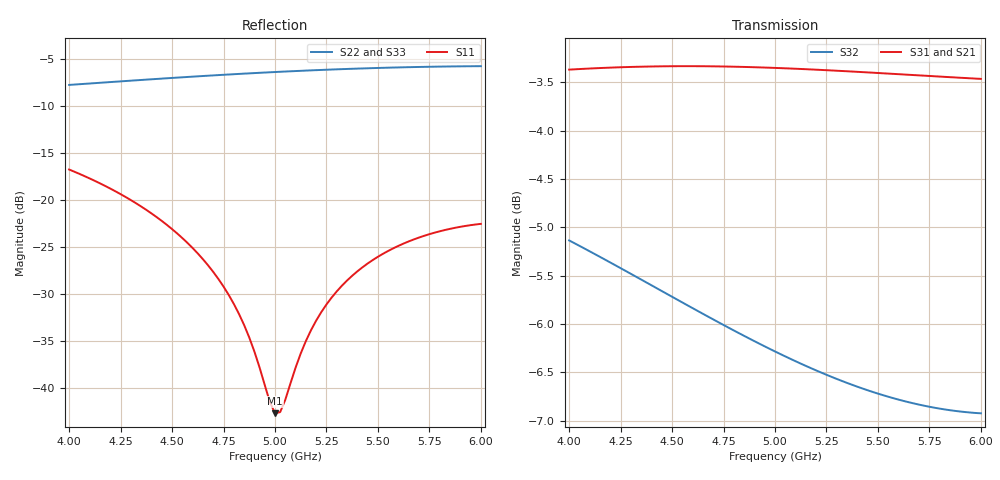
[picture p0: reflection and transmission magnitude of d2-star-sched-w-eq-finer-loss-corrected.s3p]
! yapnr Order 0 prediction d2-star-sched-w-eq-finer: predictions/D2/runs/d2-star-sched/finer.s3p, loss-corrected
! substrate W-eq; coupon model OSHPARK-4L-FR408HR; correction: ratio (port line)
! |S21|, |S31| (and S12, S13) scaled, phases kept; 50 ohm, e^(+jwt)
# GHz S RI R 50
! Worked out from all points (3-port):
!   81 points, 4 GHz to 6 GHz, reference 50 ohm
!   strongest paths, dB at 4 GHz, 4.5 GHz, 5 GHz, 5.5 GHz, 6 GHz:
!     S31: -3.4, -3.3, -3.4, -3.4, -3.5
!     S21: -3.4, -3.3, -3.4, -3.4, -3.5
!     S32: -5.1, -5.7, -6.3, -6.7, -6.9
!   lowest |S11| = -42.7 dB at 5 GHz (marker M1), VSWR 1.01, Z = 49.7 + j0.675 ohm
!   |S11| at or under -10 dB: start of sweep to end of sweep
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4  0.0376 0.1407  -0.6595 -0.1602  -0.6595 -0.1602
   -0.6593 -0.1607  0.3541 -0.2086  -0.4548 0.3158
   -0.6593 -0.1607  -0.4548 0.3158  0.3541 -0.2086
4.375  0.0419 0.0782  -0.6795 0.0395  -0.6795 0.0395
       -0.68 0.0385  0.2757 -0.3411  -0.3106 0.4253
       -0.68 0.0385  -0.3106 0.4253  0.2757 -0.3411
4.65  0.0281 0.0395  -0.6545 0.1863  -0.6545 0.1863
      -0.6557 0.1852  0.1915 -0.4165  -0.1956 0.4681
      -0.6557 0.1852  -0.1956 0.4681  0.1915 -0.4165
4.825  0.0139 0.0205  -0.6215 0.2754  -0.6215 0.2754
       -0.6231 0.2745  0.1292 -0.4523  -0.123 0.4803
       -0.6231 0.2745  -0.123 0.4803  0.1292 -0.4523
5  -0.00274 0.00679  -0.5759 0.3588  -0.5759 0.3588
   -0.578 0.3582  0.0621 -0.4774  -0.0527 0.4822
   -0.578 0.3582  -0.0527 0.4822  0.0621 -0.4774
5.025  -0.00522 0.00528  -0.5684 0.3702  -0.5684 0.3702
       -0.5706 0.3696  0.0522 -0.48  -0.0429 0.4818
       -0.5706 0.3696  -0.0429 0.4818  0.0522 -0.48
5.2  -0.0227 -0.00215  -0.51 0.4448  -0.51 0.4448
     -0.5125 0.4448  -0.0181 -0.4923  0.0234 0.4737
     -0.5125 0.4448  0.0234 0.4737  -0.0181 -0.4923
5.375  -0.0393 -0.00438  -0.4417 0.5102  -0.4417 0.5102
       -0.4444 0.5108  -0.0891 -0.493  0.0855 0.4583
       -0.4444 0.5108  0.0855 0.4583  -0.0891 -0.493
5.65  -0.0603 0.000715  -0.3182 0.5916  -0.3182 0.5916
      -0.3208 0.5933  -0.1975 -0.4712  0.1743 0.422
      -0.3208 0.5933  0.1743 0.422  -0.1975 -0.4712
6  -0.0731 0.0157  -0.1412 0.6528  -0.1412 0.6528
   -0.1428 0.6558  -0.3198 -0.4065  0.2725 0.359
   -0.1428 0.6558  0.2725 0.359  -0.3198 -0.4065
